VERSION 5.7 ;
  NAMESCASESENSITIVE ON ;
  NOWIREEXTENSIONATPIN ON ;
  DIVIDERCHAR "/" ;
  BUSBITCHARS "[]" ;
UNITS
  DATABASE MICRONS 200 ;
END UNITS

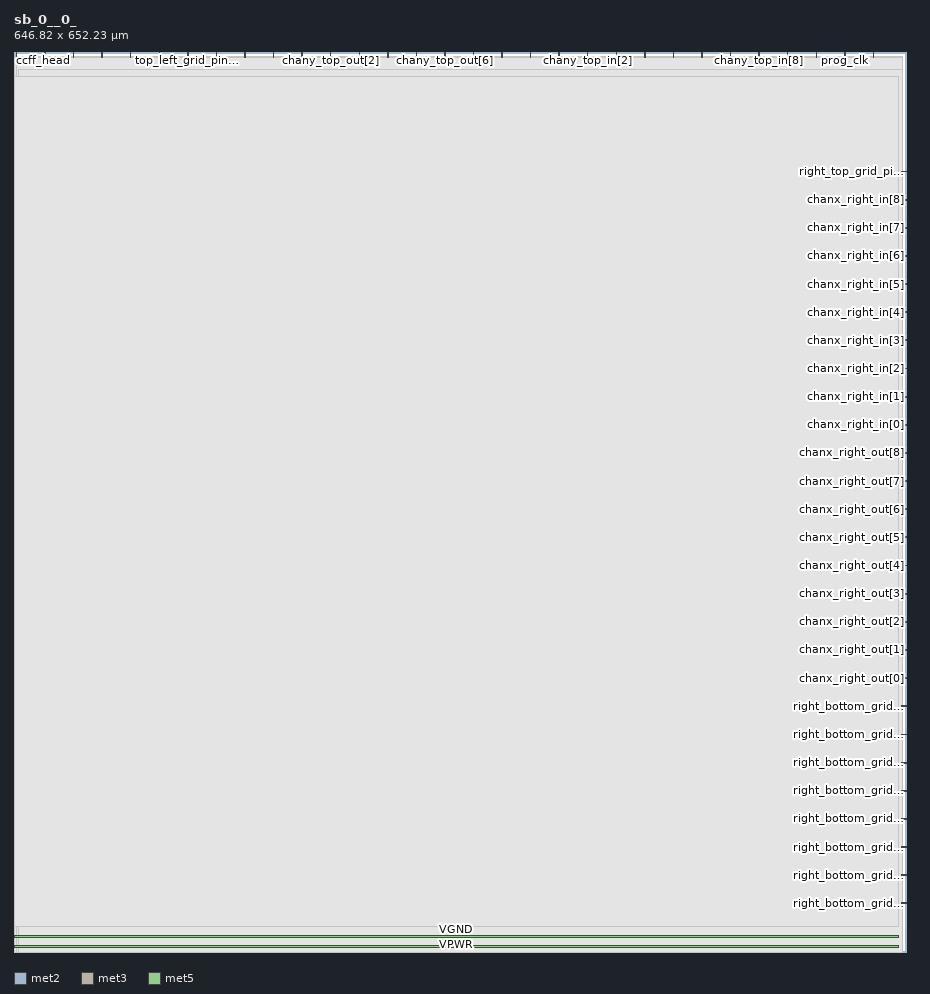
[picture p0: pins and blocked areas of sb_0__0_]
MACRO sb_0__0_
  CLASS BLOCK ;
  FOREIGN sb_0__0_ ;
  ORIGIN 0.000 0.000 ;
  SIZE 646.820 BY 652.230 ;
  PIN ccff_head
    DIRECTION INPUT ;
    PORT
      LAYER met2 ;
        RECT 1.660 648.230 1.940 652.230 ;
    END
  END ccff_head
  PIN top_left_grid_pin_1_
    DIRECTION INPUT ;
    PORT
      LAYER met2 ;
        RECT 22.360 648.230 22.640 652.230 ;
    END
  END top_left_grid_pin_1_
  PIN top_left_grid_pin_3_
    DIRECTION INPUT ;
    PORT
      LAYER met2 ;
        RECT 43.060 648.230 43.340 652.230 ;
    END
  END top_left_grid_pin_3_
  PIN top_left_grid_pin_5_
    DIRECTION INPUT ;
    PORT
      LAYER met2 ;
        RECT 63.760 648.230 64.040 652.230 ;
    END
  END top_left_grid_pin_5_
  PIN top_left_grid_pin_7_
    DIRECTION INPUT ;
    PORT
      LAYER met2 ;
        RECT 84.460 648.230 84.740 652.230 ;
    END
  END top_left_grid_pin_7_
  PIN top_left_grid_pin_9_
    DIRECTION INPUT ;
    PORT
      LAYER met2 ;
        RECT 105.160 648.230 105.440 652.230 ;
    END
  END top_left_grid_pin_9_
  PIN top_left_grid_pin_11_
    DIRECTION INPUT ;
    PORT
      LAYER met2 ;
        RECT 125.860 648.230 126.140 652.230 ;
    END
  END top_left_grid_pin_11_
  PIN top_left_grid_pin_13_
    DIRECTION INPUT ;
    PORT
      LAYER met2 ;
        RECT 146.560 648.230 146.840 652.230 ;
    END
  END top_left_grid_pin_13_
  PIN top_left_grid_pin_15_
    DIRECTION OUTPUT TRISTATE ;
    PORT
      LAYER met2 ;
        RECT 167.260 648.230 167.540 652.230 ;
    END
  END top_left_grid_pin_15_
  PIN chany_top_out[0]
    DIRECTION OUTPUT TRISTATE ;
    PORT
      LAYER met2 ;
        RECT 187.960 648.230 188.240 652.230 ;
    END
  END chany_top_out[0]
  PIN chany_top_out[1]
    DIRECTION OUTPUT TRISTATE ;
    PORT
      LAYER met2 ;
        RECT 208.660 648.230 208.940 652.230 ;
    END
  END chany_top_out[1]
  PIN chany_top_out[2]
    DIRECTION OUTPUT TRISTATE ;
    PORT
      LAYER met2 ;
        RECT 229.360 648.230 229.640 652.230 ;
    END
  END chany_top_out[2]
  PIN chany_top_out[3]
    DIRECTION OUTPUT TRISTATE ;
    PORT
      LAYER met2 ;
        RECT 250.060 648.230 250.340 652.230 ;
    END
  END chany_top_out[3]
  PIN chany_top_out[4]
    DIRECTION OUTPUT TRISTATE ;
    PORT
      LAYER met2 ;
        RECT 270.760 648.230 271.040 652.230 ;
    END
  END chany_top_out[4]
  PIN chany_top_out[5]
    DIRECTION OUTPUT TRISTATE ;
    PORT
      LAYER met2 ;
        RECT 291.460 648.230 291.740 652.230 ;
    END
  END chany_top_out[5]
  PIN chany_top_out[6]
    DIRECTION OUTPUT TRISTATE ;
    PORT
      LAYER met2 ;
        RECT 312.160 648.230 312.440 652.230 ;
    END
  END chany_top_out[6]
  PIN chany_top_out[7]
    DIRECTION OUTPUT TRISTATE ;
    PORT
      LAYER met2 ;
        RECT 332.860 648.230 333.140 652.230 ;
    END
  END chany_top_out[7]
  PIN chany_top_out[8]
    DIRECTION OUTPUT TRISTATE ;
    PORT
      LAYER met2 ;
        RECT 353.560 648.230 353.840 652.230 ;
    END
  END chany_top_out[8]
  PIN chany_top_in[0]
    DIRECTION INPUT ;
    PORT
      LAYER met2 ;
        RECT 374.260 648.230 374.540 652.230 ;
    END
  END chany_top_in[0]
  PIN chany_top_in[1]
    DIRECTION INPUT ;
    PORT
      LAYER met2 ;
        RECT 394.960 648.230 395.240 652.230 ;
    END
  END chany_top_in[1]
  PIN chany_top_in[2]
    DIRECTION INPUT ;
    PORT
      LAYER met2 ;
        RECT 415.660 648.230 415.940 652.230 ;
    END
  END chany_top_in[2]
  PIN chany_top_in[3]
    DIRECTION INPUT ;
    PORT
      LAYER met2 ;
        RECT 436.360 648.230 436.640 652.230 ;
    END
  END chany_top_in[3]
  PIN chany_top_in[4]
    DIRECTION INPUT ;
    PORT
      LAYER met2 ;
        RECT 457.060 648.230 457.340 652.230 ;
    END
  END chany_top_in[4]
  PIN chany_top_in[5]
    DIRECTION INPUT ;
    PORT
      LAYER met2 ;
        RECT 477.760 648.230 478.040 652.230 ;
    END
  END chany_top_in[5]
  PIN chany_top_in[6]
    DIRECTION INPUT ;
    PORT
      LAYER met2 ;
        RECT 498.460 648.230 498.740 652.230 ;
    END
  END chany_top_in[6]
  PIN chany_top_in[7]
    DIRECTION INPUT ;
    PORT
      LAYER met2 ;
        RECT 519.160 648.230 519.440 652.230 ;
    END
  END chany_top_in[7]
  PIN chany_top_in[8]
    DIRECTION INPUT ;
    PORT
      LAYER met2 ;
        RECT 539.860 648.230 540.140 652.230 ;
    END
  END chany_top_in[8]
  PIN ccff_tail
    DIRECTION OUTPUT TRISTATE ;
    PORT
      LAYER met2 ;
        RECT 560.560 648.230 560.840 652.230 ;
    END
  END ccff_tail
  PIN pReset
    DIRECTION INPUT ;
    PORT
      LAYER met2 ;
        RECT 581.260 648.230 581.540 652.230 ;
    END
  END pReset
  PIN prog_clk
    DIRECTION INPUT ;
    PORT
      LAYER met2 ;
        RECT 601.960 648.230 602.240 652.230 ;
    END
  END prog_clk
  PIN top_right_grid_pin_11_
    DIRECTION INPUT ;
    PORT
      LAYER met2 ;
        RECT 622.660 648.230 622.940 652.230 ;
    END
  END top_right_grid_pin_11_
  PIN right_bottom_grid_pin_1_
    DIRECTION INPUT ;
    PORT
      LAYER met3 ;
        RECT 642.820 34.960 646.820 35.560 ;
    END
  END right_bottom_grid_pin_1_
  PIN right_bottom_grid_pin_3_
    DIRECTION INPUT ;
    PORT
      LAYER met3 ;
        RECT 642.820 55.360 646.820 55.960 ;
    END
  END right_bottom_grid_pin_3_
  PIN right_bottom_grid_pin_5_
    DIRECTION INPUT ;
    PORT
      LAYER met3 ;
        RECT 642.820 75.760 646.820 76.360 ;
    END
  END right_bottom_grid_pin_5_
  PIN right_bottom_grid_pin_7_
    DIRECTION INPUT ;
    PORT
      LAYER met3 ;
        RECT 642.820 96.160 646.820 96.760 ;
    END
  END right_bottom_grid_pin_7_
  PIN right_bottom_grid_pin_9_
    DIRECTION INPUT ;
    PORT
      LAYER met3 ;
        RECT 642.820 116.560 646.820 117.160 ;
    END
  END right_bottom_grid_pin_9_
  PIN right_bottom_grid_pin_11_
    DIRECTION INPUT ;
    PORT
      LAYER met3 ;
        RECT 642.820 136.960 646.820 137.560 ;
    END
  END right_bottom_grid_pin_11_
  PIN right_bottom_grid_pin_13_
    DIRECTION INPUT ;
    PORT
      LAYER met3 ;
        RECT 642.820 157.360 646.820 157.960 ;
    END
  END right_bottom_grid_pin_13_
  PIN right_bottom_grid_pin_15_
    DIRECTION INPUT ;
    PORT
      LAYER met3 ;
        RECT 642.820 177.760 646.820 178.360 ;
    END
  END right_bottom_grid_pin_15_
  PIN chanx_right_out[0]
    DIRECTION OUTPUT TRISTATE ;
    PORT
      LAYER met3 ;
        RECT 642.820 198.160 646.820 198.760 ;
    END
  END chanx_right_out[0]
  PIN chanx_right_out[1]
    DIRECTION OUTPUT TRISTATE ;
    PORT
      LAYER met3 ;
        RECT 642.820 218.560 646.820 219.160 ;
    END
  END chanx_right_out[1]
  PIN chanx_right_out[2]
    DIRECTION OUTPUT TRISTATE ;
    PORT
      LAYER met3 ;
        RECT 642.820 238.960 646.820 239.560 ;
    END
  END chanx_right_out[2]
  PIN chanx_right_out[3]
    DIRECTION OUTPUT TRISTATE ;
    PORT
      LAYER met3 ;
        RECT 642.820 259.360 646.820 259.960 ;
    END
  END chanx_right_out[3]
  PIN chanx_right_out[4]
    DIRECTION OUTPUT TRISTATE ;
    PORT
      LAYER met3 ;
        RECT 642.820 279.760 646.820 280.360 ;
    END
  END chanx_right_out[4]
  PIN chanx_right_out[5]
    DIRECTION OUTPUT TRISTATE ;
    PORT
      LAYER met3 ;
        RECT 642.820 300.160 646.820 300.760 ;
    END
  END chanx_right_out[5]
  PIN chanx_right_out[6]
    DIRECTION OUTPUT TRISTATE ;
    PORT
      LAYER met3 ;
        RECT 642.820 320.560 646.820 321.160 ;
    END
  END chanx_right_out[6]
  PIN chanx_right_out[7]
    DIRECTION OUTPUT TRISTATE ;
    PORT
      LAYER met3 ;
        RECT 642.820 340.960 646.820 341.560 ;
    END
  END chanx_right_out[7]
  PIN chanx_right_out[8]
    DIRECTION OUTPUT TRISTATE ;
    PORT
      LAYER met3 ;
        RECT 642.820 361.360 646.820 361.960 ;
    END
  END chanx_right_out[8]
  PIN chanx_right_in[0]
    DIRECTION INPUT ;
    PORT
      LAYER met3 ;
        RECT 642.820 381.760 646.820 382.360 ;
    END
  END chanx_right_in[0]
  PIN chanx_right_in[1]
    DIRECTION INPUT ;
    PORT
      LAYER met3 ;
        RECT 642.820 402.160 646.820 402.760 ;
    END
  END chanx_right_in[1]
  PIN chanx_right_in[2]
    DIRECTION INPUT ;
    PORT
      LAYER met3 ;
        RECT 642.820 422.560 646.820 423.160 ;
    END
  END chanx_right_in[2]
  PIN chanx_right_in[3]
    DIRECTION INPUT ;
    PORT
      LAYER met3 ;
        RECT 642.820 442.960 646.820 443.560 ;
    END
  END chanx_right_in[3]
  PIN chanx_right_in[4]
    DIRECTION INPUT ;
    PORT
      LAYER met3 ;
        RECT 642.820 463.360 646.820 463.960 ;
    END
  END chanx_right_in[4]
  PIN chanx_right_in[5]
    DIRECTION INPUT ;
    PORT
      LAYER met3 ;
        RECT 642.820 483.760 646.820 484.360 ;
    END
  END chanx_right_in[5]
  PIN chanx_right_in[6]
    DIRECTION INPUT ;
    PORT
      LAYER met3 ;
        RECT 642.820 504.160 646.820 504.760 ;
    END
  END chanx_right_in[6]
  PIN chanx_right_in[7]
    DIRECTION INPUT ;
    PORT
      LAYER met3 ;
        RECT 642.820 524.560 646.820 525.160 ;
    END
  END chanx_right_in[7]
  PIN chanx_right_in[8]
    DIRECTION INPUT ;
    PORT
      LAYER met3 ;
        RECT 642.820 544.960 646.820 545.560 ;
    END
  END chanx_right_in[8]
  PIN right_top_grid_pin_10_
    DIRECTION INPUT ;
    PORT
      LAYER met3 ;
        RECT 642.820 565.360 646.820 565.960 ;
    END
  END right_top_grid_pin_10_
  PIN VPWR
    DIRECTION INPUT ;
    USE POWER ;
    PORT
      LAYER met5 ;
        RECT 0.190 3.200 640.970 4.800 ;
    END
  END VPWR
  PIN VGND
    DIRECTION INPUT ;
    USE GROUND ;
    PORT
      LAYER met5 ;
        RECT 0.190 10.700 640.970 12.300 ;
    END
  END VGND
  OBS
      LAYER li1 ;
        RECT 0.190 0.155 640.970 639.525 ;
      LAYER met1 ;
        RECT 0.190 0.000 643.660 648.580 ;
      LAYER met2 ;
        RECT 2.220 647.950 22.080 648.690 ;
        RECT 22.920 647.950 42.780 648.690 ;
        RECT 43.620 647.950 63.480 648.690 ;
        RECT 64.320 647.950 84.180 648.690 ;
        RECT 85.020 647.950 104.880 648.690 ;
        RECT 105.720 647.950 125.580 648.690 ;
        RECT 126.420 647.950 146.280 648.690 ;
        RECT 147.120 647.950 166.980 648.690 ;
        RECT 167.820 647.950 187.680 648.690 ;
        RECT 188.520 647.950 208.380 648.690 ;
        RECT 209.220 647.950 229.080 648.690 ;
        RECT 229.920 647.950 249.780 648.690 ;
        RECT 250.620 647.950 270.480 648.690 ;
        RECT 271.320 647.950 291.180 648.690 ;
        RECT 292.020 647.950 311.880 648.690 ;
        RECT 312.720 647.950 332.580 648.690 ;
        RECT 333.420 647.950 353.280 648.690 ;
        RECT 354.120 647.950 373.980 648.690 ;
        RECT 374.820 647.950 394.680 648.690 ;
        RECT 395.520 647.950 415.380 648.690 ;
        RECT 416.220 647.950 436.080 648.690 ;
        RECT 436.920 647.950 456.780 648.690 ;
        RECT 457.620 647.950 477.480 648.690 ;
        RECT 478.320 647.950 498.180 648.690 ;
        RECT 499.020 647.950 518.880 648.690 ;
        RECT 519.720 647.950 539.580 648.690 ;
        RECT 540.420 647.950 560.280 648.690 ;
        RECT 561.120 647.950 580.980 648.690 ;
        RECT 581.820 647.950 601.680 648.690 ;
        RECT 602.520 647.950 622.380 648.690 ;
        RECT 623.220 647.950 643.640 648.690 ;
        RECT 1.730 0.000 643.640 647.950 ;
      LAYER met3 ;
        RECT 3.390 566.360 643.880 639.605 ;
        RECT 3.390 564.960 642.420 566.360 ;
        RECT 3.390 545.960 643.880 564.960 ;
        RECT 3.390 544.560 642.420 545.960 ;
        RECT 3.390 525.560 643.880 544.560 ;
        RECT 3.390 524.160 642.420 525.560 ;
        RECT 3.390 505.160 643.880 524.160 ;
        RECT 3.390 503.760 642.420 505.160 ;
        RECT 3.390 484.760 643.880 503.760 ;
        RECT 3.390 483.360 642.420 484.760 ;
        RECT 3.390 464.360 643.880 483.360 ;
        RECT 3.390 462.960 642.420 464.360 ;
        RECT 3.390 443.960 643.880 462.960 ;
        RECT 3.390 442.560 642.420 443.960 ;
        RECT 3.390 423.560 643.880 442.560 ;
        RECT 3.390 422.160 642.420 423.560 ;
        RECT 3.390 403.160 643.880 422.160 ;
        RECT 3.390 401.760 642.420 403.160 ;
        RECT 3.390 382.760 643.880 401.760 ;
        RECT 3.390 381.360 642.420 382.760 ;
        RECT 3.390 362.360 643.880 381.360 ;
        RECT 3.390 360.960 642.420 362.360 ;
        RECT 3.390 341.960 643.880 360.960 ;
        RECT 3.390 340.560 642.420 341.960 ;
        RECT 3.390 321.560 643.880 340.560 ;
        RECT 3.390 320.160 642.420 321.560 ;
        RECT 3.390 301.160 643.880 320.160 ;
        RECT 3.390 299.760 642.420 301.160 ;
        RECT 3.390 280.760 643.880 299.760 ;
        RECT 3.390 279.360 642.420 280.760 ;
        RECT 3.390 260.360 643.880 279.360 ;
        RECT 3.390 258.960 642.420 260.360 ;
        RECT 3.390 239.960 643.880 258.960 ;
        RECT 3.390 238.560 642.420 239.960 ;
        RECT 3.390 219.560 643.880 238.560 ;
        RECT 3.390 218.160 642.420 219.560 ;
        RECT 3.390 199.160 643.880 218.160 ;
        RECT 3.390 197.760 642.420 199.160 ;
        RECT 3.390 178.760 643.880 197.760 ;
        RECT 3.390 177.360 642.420 178.760 ;
        RECT 3.390 158.360 643.880 177.360 ;
        RECT 3.390 156.960 642.420 158.360 ;
        RECT 3.390 137.960 643.880 156.960 ;
        RECT 3.390 136.560 642.420 137.960 ;
        RECT 3.390 117.560 643.880 136.560 ;
        RECT 3.390 116.160 642.420 117.560 ;
        RECT 3.390 97.160 643.880 116.160 ;
        RECT 3.390 95.760 642.420 97.160 ;
        RECT 3.390 76.760 643.880 95.760 ;
        RECT 3.390 75.360 642.420 76.760 ;
        RECT 3.390 56.360 643.880 75.360 ;
        RECT 3.390 54.960 642.420 56.360 ;
        RECT 3.390 35.960 643.880 54.960 ;
        RECT 3.390 34.560 642.420 35.960 ;
        RECT 3.390 0.075 643.880 34.560 ;
      LAYER met4 ;
        RECT 3.390 0.000 643.895 639.680 ;
      LAYER met5 ;
        RECT 0.190 18.200 640.970 634.800 ;
  END
END sb_0__0_
END LIBRARY

